VERSION 5.7 ;
  NOWIREEXTENSIONATPIN ON ;
  DIVIDERCHAR "/" ;
  BUSBITCHARS "[]" ;
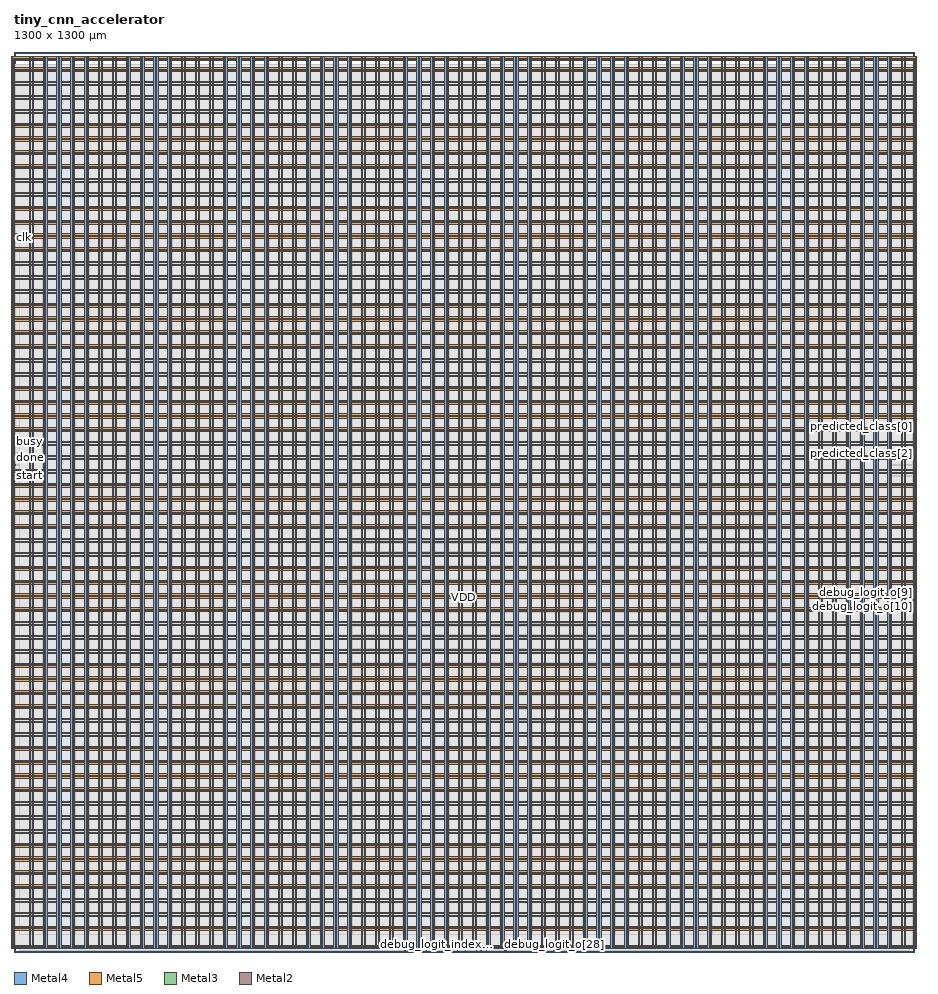
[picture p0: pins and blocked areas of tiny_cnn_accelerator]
MACRO tiny_cnn_accelerator
  CLASS BLOCK ;
  FOREIGN tiny_cnn_accelerator ;
  ORIGIN 0.000 0.000 ;
  SIZE 1300.000 BY 1300.000 ;
  PIN VDD
    DIRECTION INOUT ;
    USE POWER ;
    PORT
      LAYER Metal4 ;
        RECT -1.280 7.680 0.720 1289.840 ;
    END
    PORT
      LAYER Metal4 ;
        RECT 1299.040 7.680 1301.040 1289.840 ;
    END
    PORT
      LAYER Metal5 ;
        RECT -1.280 7.680 1301.040 9.680 ;
    END
    PORT
      LAYER Metal5 ;
        RECT -1.280 1287.840 1301.040 1289.840 ;
    END
    PORT
      LAYER Metal4 ;
        RECT 22.040 4.680 24.040 1292.840 ;
    END
    PORT
      LAYER Metal4 ;
        RECT 42.040 4.680 44.040 1292.840 ;
    END
    PORT
      LAYER Metal4 ;
        RECT 62.040 4.680 64.040 1292.840 ;
    END
    PORT
      LAYER Metal4 ;
        RECT 82.040 4.680 84.040 1292.840 ;
    END
    PORT
      LAYER Metal4 ;
        RECT 102.040 4.680 104.040 1292.840 ;
    END
    PORT
      LAYER Metal4 ;
        RECT 122.040 4.680 124.040 1292.840 ;
    END
    PORT
      LAYER Metal4 ;
        RECT 142.040 4.680 144.040 1292.840 ;
    END
    PORT
      LAYER Metal4 ;
        RECT 162.040 4.680 164.040 1292.840 ;
    END
    PORT
      LAYER Metal4 ;
        RECT 182.040 4.680 184.040 1292.840 ;
    END
    PORT
      LAYER Metal4 ;
        RECT 202.040 4.680 204.040 1292.840 ;
    END
    PORT
      LAYER Metal4 ;
        RECT 222.040 4.680 224.040 1292.840 ;
    END
    PORT
      LAYER Metal4 ;
        RECT 242.040 4.680 244.040 1292.840 ;
    END
    PORT
      LAYER Metal4 ;
        RECT 262.040 4.680 264.040 1292.840 ;
    END
    PORT
      LAYER Metal4 ;
        RECT 282.040 4.680 284.040 1292.840 ;
    END
    PORT
      LAYER Metal4 ;
        RECT 302.040 4.680 304.040 1292.840 ;
    END
    PORT
      LAYER Metal4 ;
        RECT 322.040 4.680 324.040 1292.840 ;
    END
    PORT
      LAYER Metal4 ;
        RECT 342.040 4.680 344.040 1292.840 ;
    END
    PORT
      LAYER Metal4 ;
        RECT 362.040 4.680 364.040 1292.840 ;
    END
    PORT
      LAYER Metal4 ;
        RECT 382.040 4.680 384.040 1292.840 ;
    END
    PORT
      LAYER Metal4 ;
        RECT 402.040 4.680 404.040 1292.840 ;
    END
    PORT
      LAYER Metal4 ;
        RECT 422.040 4.680 424.040 1292.840 ;
    END
    PORT
      LAYER Metal4 ;
        RECT 442.040 4.680 444.040 1292.840 ;
    END
    PORT
      LAYER Metal4 ;
        RECT 462.040 4.680 464.040 1292.840 ;
    END
    PORT
      LAYER Metal4 ;
        RECT 482.040 4.680 484.040 1292.840 ;
    END
    PORT
      LAYER Metal4 ;
        RECT 502.040 4.680 504.040 1292.840 ;
    END
    PORT
      LAYER Metal4 ;
        RECT 522.040 4.680 524.040 1292.840 ;
    END
    PORT
      LAYER Metal4 ;
        RECT 542.040 4.680 544.040 1292.840 ;
    END
    PORT
      LAYER Metal4 ;
        RECT 562.040 4.680 564.040 1292.840 ;
    END
    PORT
      LAYER Metal4 ;
        RECT 582.040 4.680 584.040 1292.840 ;
    END
    PORT
      LAYER Metal4 ;
        RECT 602.040 4.680 604.040 1292.840 ;
    END
    PORT
      LAYER Metal4 ;
        RECT 622.040 4.680 624.040 1292.840 ;
    END
    PORT
      LAYER Metal4 ;
        RECT 642.040 4.680 644.040 1292.840 ;
    END
    PORT
      LAYER Metal4 ;
        RECT 662.040 4.680 664.040 1292.840 ;
    END
    PORT
      LAYER Metal4 ;
        RECT 682.040 4.680 684.040 1292.840 ;
    END
    PORT
      LAYER Metal4 ;
        RECT 702.040 4.680 704.040 1292.840 ;
    END
    PORT
      LAYER Metal4 ;
        RECT 722.040 4.680 724.040 1292.840 ;
    END
    PORT
      LAYER Metal4 ;
        RECT 742.040 4.680 744.040 1292.840 ;
    END
    PORT
      LAYER Metal4 ;
        RECT 762.040 4.680 764.040 1292.840 ;
    END
    PORT
      LAYER Metal4 ;
        RECT 782.040 4.680 784.040 1292.840 ;
    END
    PORT
      LAYER Metal4 ;
        RECT 802.040 4.680 804.040 1292.840 ;
    END
    PORT
      LAYER Metal4 ;
        RECT 822.040 4.680 824.040 1292.840 ;
    END
    PORT
      LAYER Metal4 ;
        RECT 842.040 4.680 844.040 1292.840 ;
    END
    PORT
      LAYER Metal4 ;
        RECT 862.040 4.680 864.040 1292.840 ;
    END
    PORT
      LAYER Metal4 ;
        RECT 882.040 4.680 884.040 1292.840 ;
    END
    PORT
      LAYER Metal4 ;
        RECT 902.040 4.680 904.040 1292.840 ;
    END
    PORT
      LAYER Metal4 ;
        RECT 922.040 4.680 924.040 1292.840 ;
    END
    PORT
      LAYER Metal4 ;
        RECT 942.040 4.680 944.040 1292.840 ;
    END
    PORT
      LAYER Metal4 ;
        RECT 962.040 4.680 964.040 1292.840 ;
    END
    PORT
      LAYER Metal4 ;
        RECT 982.040 4.680 984.040 1292.840 ;
    END
    PORT
      LAYER Metal4 ;
        RECT 1002.040 4.680 1004.040 1292.840 ;
    END
    PORT
      LAYER Metal4 ;
        RECT 1022.040 4.680 1024.040 1292.840 ;
    END
    PORT
      LAYER Metal4 ;
        RECT 1042.040 4.680 1044.040 1292.840 ;
    END
    PORT
      LAYER Metal4 ;
        RECT 1062.040 4.680 1064.040 1292.840 ;
    END
    PORT
      LAYER Metal4 ;
        RECT 1082.040 4.680 1084.040 1292.840 ;
    END
    PORT
      LAYER Metal4 ;
        RECT 1102.040 4.680 1104.040 1292.840 ;
    END
    PORT
      LAYER Metal4 ;
        RECT 1122.040 4.680 1124.040 1292.840 ;
    END
    PORT
      LAYER Metal4 ;
        RECT 1142.040 4.680 1144.040 1292.840 ;
    END
    PORT
      LAYER Metal4 ;
        RECT 1162.040 4.680 1164.040 1292.840 ;
    END
    PORT
      LAYER Metal4 ;
        RECT 1182.040 4.680 1184.040 1292.840 ;
    END
    PORT
      LAYER Metal4 ;
        RECT 1202.040 4.680 1204.040 1292.840 ;
    END
    PORT
      LAYER Metal4 ;
        RECT 1222.040 4.680 1224.040 1292.840 ;
    END
    PORT
      LAYER Metal4 ;
        RECT 1242.040 4.680 1244.040 1292.840 ;
    END
    PORT
      LAYER Metal4 ;
        RECT 1262.040 4.680 1264.040 1292.840 ;
    END
    PORT
      LAYER Metal4 ;
        RECT 1282.040 4.680 1284.040 1292.840 ;
    END
    PORT
      LAYER Metal5 ;
        RECT -4.280 31.330 1304.040 33.330 ;
    END
    PORT
      LAYER Metal5 ;
        RECT -4.280 51.330 1304.040 53.330 ;
    END
    PORT
      LAYER Metal5 ;
        RECT -4.280 71.330 1304.040 73.330 ;
    END
    PORT
      LAYER Metal5 ;
        RECT -4.280 91.330 1304.040 93.330 ;
    END
    PORT
      LAYER Metal5 ;
        RECT -4.280 111.330 1304.040 113.330 ;
    END
    PORT
      LAYER Metal5 ;
        RECT -4.280 131.330 1304.040 133.330 ;
    END
    PORT
      LAYER Metal5 ;
        RECT -4.280 151.330 1304.040 153.330 ;
    END
    PORT
      LAYER Metal5 ;
        RECT -4.280 171.330 1304.040 173.330 ;
    END
    PORT
      LAYER Metal5 ;
        RECT -4.280 191.330 1304.040 193.330 ;
    END
    PORT
      LAYER Metal5 ;
        RECT -4.280 211.330 1304.040 213.330 ;
    END
    PORT
      LAYER Metal5 ;
        RECT -4.280 231.330 1304.040 233.330 ;
    END
    PORT
      LAYER Metal5 ;
        RECT -4.280 251.330 1304.040 253.330 ;
    END
    PORT
      LAYER Metal5 ;
        RECT -4.280 271.330 1304.040 273.330 ;
    END
    PORT
      LAYER Metal5 ;
        RECT -4.280 291.330 1304.040 293.330 ;
    END
    PORT
      LAYER Metal5 ;
        RECT -4.280 311.330 1304.040 313.330 ;
    END
    PORT
      LAYER Metal5 ;
        RECT -4.280 331.330 1304.040 333.330 ;
    END
    PORT
      LAYER Metal5 ;
        RECT -4.280 351.330 1304.040 353.330 ;
    END
    PORT
      LAYER Metal5 ;
        RECT -4.280 371.330 1304.040 373.330 ;
    END
    PORT
      LAYER Metal5 ;
        RECT -4.280 391.330 1304.040 393.330 ;
    END
    PORT
      LAYER Metal5 ;
        RECT -4.280 411.330 1304.040 413.330 ;
    END
    PORT
      LAYER Metal5 ;
        RECT -4.280 431.330 1304.040 433.330 ;
    END
    PORT
      LAYER Metal5 ;
        RECT -4.280 451.330 1304.040 453.330 ;
    END
    PORT
      LAYER Metal5 ;
        RECT -4.280 471.330 1304.040 473.330 ;
    END
    PORT
      LAYER Metal5 ;
        RECT -4.280 491.330 1304.040 493.330 ;
    END
    PORT
      LAYER Metal5 ;
        RECT -4.280 511.330 1304.040 513.330 ;
    END
    PORT
      LAYER Metal5 ;
        RECT -4.280 531.330 1304.040 533.330 ;
    END
    PORT
      LAYER Metal5 ;
        RECT -4.280 551.330 1304.040 553.330 ;
    END
    PORT
      LAYER Metal5 ;
        RECT -4.280 571.330 1304.040 573.330 ;
    END
    PORT
      LAYER Metal5 ;
        RECT -4.280 591.330 1304.040 593.330 ;
    END
    PORT
      LAYER Metal5 ;
        RECT -4.280 611.330 1304.040 613.330 ;
    END
    PORT
      LAYER Metal5 ;
        RECT -4.280 631.330 1304.040 633.330 ;
    END
    PORT
      LAYER Metal5 ;
        RECT -4.280 651.330 1304.040 653.330 ;
    END
    PORT
      LAYER Metal5 ;
        RECT -4.280 671.330 1304.040 673.330 ;
    END
    PORT
      LAYER Metal5 ;
        RECT -4.280 691.330 1304.040 693.330 ;
    END
    PORT
      LAYER Metal5 ;
        RECT -4.280 711.330 1304.040 713.330 ;
    END
    PORT
      LAYER Metal5 ;
        RECT -4.280 731.330 1304.040 733.330 ;
    END
    PORT
      LAYER Metal5 ;
        RECT -4.280 751.330 1304.040 753.330 ;
    END
    PORT
      LAYER Metal5 ;
        RECT -4.280 771.330 1304.040 773.330 ;
    END
    PORT
      LAYER Metal5 ;
        RECT -4.280 791.330 1304.040 793.330 ;
    END
    PORT
      LAYER Metal5 ;
        RECT -4.280 811.330 1304.040 813.330 ;
    END
    PORT
      LAYER Metal5 ;
        RECT -4.280 831.330 1304.040 833.330 ;
    END
    PORT
      LAYER Metal5 ;
        RECT -4.280 851.330 1304.040 853.330 ;
    END
    PORT
      LAYER Metal5 ;
        RECT -4.280 871.330 1304.040 873.330 ;
    END
    PORT
      LAYER Metal5 ;
        RECT -4.280 891.330 1304.040 893.330 ;
    END
    PORT
      LAYER Metal5 ;
        RECT -4.280 911.330 1304.040 913.330 ;
    END
    PORT
      LAYER Metal5 ;
        RECT -4.280 931.330 1304.040 933.330 ;
    END
    PORT
      LAYER Metal5 ;
        RECT -4.280 951.330 1304.040 953.330 ;
    END
    PORT
      LAYER Metal5 ;
        RECT -4.280 971.330 1304.040 973.330 ;
    END
    PORT
      LAYER Metal5 ;
        RECT -4.280 991.330 1304.040 993.330 ;
    END
    PORT
      LAYER Metal5 ;
        RECT -4.280 1011.330 1304.040 1013.330 ;
    END
    PORT
      LAYER Metal5 ;
        RECT -4.280 1031.330 1304.040 1033.330 ;
    END
    PORT
      LAYER Metal5 ;
        RECT -4.280 1051.330 1304.040 1053.330 ;
    END
    PORT
      LAYER Metal5 ;
        RECT -4.280 1071.330 1304.040 1073.330 ;
    END
    PORT
      LAYER Metal5 ;
        RECT -4.280 1091.330 1304.040 1093.330 ;
    END
    PORT
      LAYER Metal5 ;
        RECT -4.280 1111.330 1304.040 1113.330 ;
    END
    PORT
      LAYER Metal5 ;
        RECT -4.280 1131.330 1304.040 1133.330 ;
    END
    PORT
      LAYER Metal5 ;
        RECT -4.280 1151.330 1304.040 1153.330 ;
    END
    PORT
      LAYER Metal5 ;
        RECT -4.280 1171.330 1304.040 1173.330 ;
    END
    PORT
      LAYER Metal5 ;
        RECT -4.280 1191.330 1304.040 1193.330 ;
    END
    PORT
      LAYER Metal5 ;
        RECT -4.280 1211.330 1304.040 1213.330 ;
    END
    PORT
      LAYER Metal5 ;
        RECT -4.280 1231.330 1304.040 1233.330 ;
    END
    PORT
      LAYER Metal5 ;
        RECT -4.280 1251.330 1304.040 1253.330 ;
    END
    PORT
      LAYER Metal5 ;
        RECT -4.280 1271.330 1304.040 1273.330 ;
    END
  END VDD
  PIN VSS
    DIRECTION INOUT ;
    USE GROUND ;
    PORT
      LAYER Metal4 ;
        RECT -4.280 4.680 -2.280 1292.840 ;
    END
    PORT
      LAYER Metal4 ;
        RECT 1302.040 4.680 1304.040 1292.840 ;
    END
    PORT
      LAYER Metal5 ;
        RECT -4.280 4.680 1304.040 6.680 ;
    END
    PORT
      LAYER Metal5 ;
        RECT -4.280 1290.840 1304.040 1292.840 ;
    END
    PORT
      LAYER Metal4 ;
        RECT 26.040 4.680 28.040 1292.840 ;
    END
    PORT
      LAYER Metal4 ;
        RECT 46.040 4.680 48.040 1292.840 ;
    END
    PORT
      LAYER Metal4 ;
        RECT 66.040 4.680 68.040 1292.840 ;
    END
    PORT
      LAYER Metal4 ;
        RECT 86.040 4.680 88.040 1292.840 ;
    END
    PORT
      LAYER Metal4 ;
        RECT 106.040 4.680 108.040 1292.840 ;
    END
    PORT
      LAYER Metal4 ;
        RECT 126.040 4.680 128.040 1292.840 ;
    END
    PORT
      LAYER Metal4 ;
        RECT 146.040 4.680 148.040 1292.840 ;
    END
    PORT
      LAYER Metal4 ;
        RECT 166.040 4.680 168.040 1292.840 ;
    END
    PORT
      LAYER Metal4 ;
        RECT 186.040 4.680 188.040 1292.840 ;
    END
    PORT
      LAYER Metal4 ;
        RECT 206.040 4.680 208.040 1292.840 ;
    END
    PORT
      LAYER Metal4 ;
        RECT 226.040 4.680 228.040 1292.840 ;
    END
    PORT
      LAYER Metal4 ;
        RECT 246.040 4.680 248.040 1292.840 ;
    END
    PORT
      LAYER Metal4 ;
        RECT 266.040 4.680 268.040 1292.840 ;
    END
    PORT
      LAYER Metal4 ;
        RECT 286.040 4.680 288.040 1292.840 ;
    END
    PORT
      LAYER Metal4 ;
        RECT 306.040 4.680 308.040 1292.840 ;
    END
    PORT
      LAYER Metal4 ;
        RECT 326.040 4.680 328.040 1292.840 ;
    END
    PORT
      LAYER Metal4 ;
        RECT 346.040 4.680 348.040 1292.840 ;
    END
    PORT
      LAYER Metal4 ;
        RECT 366.040 4.680 368.040 1292.840 ;
    END
    PORT
      LAYER Metal4 ;
        RECT 386.040 4.680 388.040 1292.840 ;
    END
    PORT
      LAYER Metal4 ;
        RECT 406.040 4.680 408.040 1292.840 ;
    END
    PORT
      LAYER Metal4 ;
        RECT 426.040 4.680 428.040 1292.840 ;
    END
    PORT
      LAYER Metal4 ;
        RECT 446.040 4.680 448.040 1292.840 ;
    END
    PORT
      LAYER Metal4 ;
        RECT 466.040 4.680 468.040 1292.840 ;
    END
    PORT
      LAYER Metal4 ;
        RECT 486.040 4.680 488.040 1292.840 ;
    END
    PORT
      LAYER Metal4 ;
        RECT 506.040 4.680 508.040 1292.840 ;
    END
    PORT
      LAYER Metal4 ;
        RECT 526.040 4.680 528.040 1292.840 ;
    END
    PORT
      LAYER Metal4 ;
        RECT 546.040 4.680 548.040 1292.840 ;
    END
    PORT
      LAYER Metal4 ;
        RECT 566.040 4.680 568.040 1292.840 ;
    END
    PORT
      LAYER Metal4 ;
        RECT 586.040 4.680 588.040 1292.840 ;
    END
    PORT
      LAYER Metal4 ;
        RECT 606.040 4.680 608.040 1292.840 ;
    END
    PORT
      LAYER Metal4 ;
        RECT 626.040 4.680 628.040 1292.840 ;
    END
    PORT
      LAYER Metal4 ;
        RECT 646.040 4.680 648.040 1292.840 ;
    END
    PORT
      LAYER Metal4 ;
        RECT 666.040 4.680 668.040 1292.840 ;
    END
    PORT
      LAYER Metal4 ;
        RECT 686.040 4.680 688.040 1292.840 ;
    END
    PORT
      LAYER Metal4 ;
        RECT 706.040 4.680 708.040 1292.840 ;
    END
    PORT
      LAYER Metal4 ;
        RECT 726.040 4.680 728.040 1292.840 ;
    END
    PORT
      LAYER Metal4 ;
        RECT 746.040 4.680 748.040 1292.840 ;
    END
    PORT
      LAYER Metal4 ;
        RECT 766.040 4.680 768.040 1292.840 ;
    END
    PORT
      LAYER Metal4 ;
        RECT 786.040 4.680 788.040 1292.840 ;
    END
    PORT
      LAYER Metal4 ;
        RECT 806.040 4.680 808.040 1292.840 ;
    END
    PORT
      LAYER Metal4 ;
        RECT 826.040 4.680 828.040 1292.840 ;
    END
    PORT
      LAYER Metal4 ;
        RECT 846.040 4.680 848.040 1292.840 ;
    END
    PORT
      LAYER Metal4 ;
        RECT 866.040 4.680 868.040 1292.840 ;
    END
    PORT
      LAYER Metal4 ;
        RECT 886.040 4.680 888.040 1292.840 ;
    END
    PORT
      LAYER Metal4 ;
        RECT 906.040 4.680 908.040 1292.840 ;
    END
    PORT
      LAYER Metal4 ;
        RECT 926.040 4.680 928.040 1292.840 ;
    END
    PORT
      LAYER Metal4 ;
        RECT 946.040 4.680 948.040 1292.840 ;
    END
    PORT
      LAYER Metal4 ;
        RECT 966.040 4.680 968.040 1292.840 ;
    END
    PORT
      LAYER Metal4 ;
        RECT 986.040 4.680 988.040 1292.840 ;
    END
    PORT
      LAYER Metal4 ;
        RECT 1006.040 4.680 1008.040 1292.840 ;
    END
    PORT
      LAYER Metal4 ;
        RECT 1026.040 4.680 1028.040 1292.840 ;
    END
    PORT
      LAYER Metal4 ;
        RECT 1046.040 4.680 1048.040 1292.840 ;
    END
    PORT
      LAYER Metal4 ;
        RECT 1066.040 4.680 1068.040 1292.840 ;
    END
    PORT
      LAYER Metal4 ;
        RECT 1086.040 4.680 1088.040 1292.840 ;
    END
    PORT
      LAYER Metal4 ;
        RECT 1106.040 4.680 1108.040 1292.840 ;
    END
    PORT
      LAYER Metal4 ;
        RECT 1126.040 4.680 1128.040 1292.840 ;
    END
    PORT
      LAYER Metal4 ;
        RECT 1146.040 4.680 1148.040 1292.840 ;
    END
    PORT
      LAYER Metal4 ;
        RECT 1166.040 4.680 1168.040 1292.840 ;
    END
    PORT
      LAYER Metal4 ;
        RECT 1186.040 4.680 1188.040 1292.840 ;
    END
    PORT
      LAYER Metal4 ;
        RECT 1206.040 4.680 1208.040 1292.840 ;
    END
    PORT
      LAYER Metal4 ;
        RECT 1226.040 4.680 1228.040 1292.840 ;
    END
    PORT
      LAYER Metal4 ;
        RECT 1246.040 4.680 1248.040 1292.840 ;
    END
    PORT
      LAYER Metal4 ;
        RECT 1266.040 4.680 1268.040 1292.840 ;
    END
    PORT
      LAYER Metal4 ;
        RECT 1286.040 4.680 1288.040 1292.840 ;
    END
    PORT
      LAYER Metal5 ;
        RECT -4.280 35.330 1304.040 37.330 ;
    END
    PORT
      LAYER Metal5 ;
        RECT -4.280 55.330 1304.040 57.330 ;
    END
    PORT
      LAYER Metal5 ;
        RECT -4.280 75.330 1304.040 77.330 ;
    END
    PORT
      LAYER Metal5 ;
        RECT -4.280 95.330 1304.040 97.330 ;
    END
    PORT
      LAYER Metal5 ;
        RECT -4.280 115.330 1304.040 117.330 ;
    END
    PORT
      LAYER Metal5 ;
        RECT -4.280 135.330 1304.040 137.330 ;
    END
    PORT
      LAYER Metal5 ;
        RECT -4.280 155.330 1304.040 157.330 ;
    END
    PORT
      LAYER Metal5 ;
        RECT -4.280 175.330 1304.040 177.330 ;
    END
    PORT
      LAYER Metal5 ;
        RECT -4.280 195.330 1304.040 197.330 ;
    END
    PORT
      LAYER Metal5 ;
        RECT -4.280 215.330 1304.040 217.330 ;
    END
    PORT
      LAYER Metal5 ;
        RECT -4.280 235.330 1304.040 237.330 ;
    END
    PORT
      LAYER Metal5 ;
        RECT -4.280 255.330 1304.040 257.330 ;
    END
    PORT
      LAYER Metal5 ;
        RECT -4.280 275.330 1304.040 277.330 ;
    END
    PORT
      LAYER Metal5 ;
        RECT -4.280 295.330 1304.040 297.330 ;
    END
    PORT
      LAYER Metal5 ;
        RECT -4.280 315.330 1304.040 317.330 ;
    END
    PORT
      LAYER Metal5 ;
        RECT -4.280 335.330 1304.040 337.330 ;
    END
    PORT
      LAYER Metal5 ;
        RECT -4.280 355.330 1304.040 357.330 ;
    END
    PORT
      LAYER Metal5 ;
        RECT -4.280 375.330 1304.040 377.330 ;
    END
    PORT
      LAYER Metal5 ;
        RECT -4.280 395.330 1304.040 397.330 ;
    END
    PORT
      LAYER Metal5 ;
        RECT -4.280 415.330 1304.040 417.330 ;
    END
    PORT
      LAYER Metal5 ;
        RECT -4.280 435.330 1304.040 437.330 ;
    END
    PORT
      LAYER Metal5 ;
        RECT -4.280 455.330 1304.040 457.330 ;
    END
    PORT
      LAYER Metal5 ;
        RECT -4.280 475.330 1304.040 477.330 ;
    END
    PORT
      LAYER Metal5 ;
        RECT -4.280 495.330 1304.040 497.330 ;
    END
    PORT
      LAYER Metal5 ;
        RECT -4.280 515.330 1304.040 517.330 ;
    END
    PORT
      LAYER Metal5 ;
        RECT -4.280 535.330 1304.040 537.330 ;
    END
    PORT
      LAYER Metal5 ;
        RECT -4.280 555.330 1304.040 557.330 ;
    END
    PORT
      LAYER Metal5 ;
        RECT -4.280 575.330 1304.040 577.330 ;
    END
    PORT
      LAYER Metal5 ;
        RECT -4.280 595.330 1304.040 597.330 ;
    END
    PORT
      LAYER Metal5 ;
        RECT -4.280 615.330 1304.040 617.330 ;
    END
    PORT
      LAYER Metal5 ;
        RECT -4.280 635.330 1304.040 637.330 ;
    END
    PORT
      LAYER Metal5 ;
        RECT -4.280 655.330 1304.040 657.330 ;
    END
    PORT
      LAYER Metal5 ;
        RECT -4.280 675.330 1304.040 677.330 ;
    END
    PORT
      LAYER Metal5 ;
        RECT -4.280 695.330 1304.040 697.330 ;
    END
    PORT
      LAYER Metal5 ;
        RECT -4.280 715.330 1304.040 717.330 ;
    END
    PORT
      LAYER Metal5 ;
        RECT -4.280 735.330 1304.040 737.330 ;
    END
    PORT
      LAYER Metal5 ;
        RECT -4.280 755.330 1304.040 757.330 ;
    END
    PORT
      LAYER Metal5 ;
        RECT -4.280 775.330 1304.040 777.330 ;
    END
    PORT
      LAYER Metal5 ;
        RECT -4.280 795.330 1304.040 797.330 ;
    END
    PORT
      LAYER Metal5 ;
        RECT -4.280 815.330 1304.040 817.330 ;
    END
    PORT
      LAYER Metal5 ;
        RECT -4.280 835.330 1304.040 837.330 ;
    END
    PORT
      LAYER Metal5 ;
        RECT -4.280 855.330 1304.040 857.330 ;
    END
    PORT
      LAYER Metal5 ;
        RECT -4.280 875.330 1304.040 877.330 ;
    END
    PORT
      LAYER Metal5 ;
        RECT -4.280 895.330 1304.040 897.330 ;
    END
    PORT
      LAYER Metal5 ;
        RECT -4.280 915.330 1304.040 917.330 ;
    END
    PORT
      LAYER Metal5 ;
        RECT -4.280 935.330 1304.040 937.330 ;
    END
    PORT
      LAYER Metal5 ;
        RECT -4.280 955.330 1304.040 957.330 ;
    END
    PORT
      LAYER Metal5 ;
        RECT -4.280 975.330 1304.040 977.330 ;
    END
    PORT
      LAYER Metal5 ;
        RECT -4.280 995.330 1304.040 997.330 ;
    END
    PORT
      LAYER Metal5 ;
        RECT -4.280 1015.330 1304.040 1017.330 ;
    END
    PORT
      LAYER Metal5 ;
        RECT -4.280 1035.330 1304.040 1037.330 ;
    END
    PORT
      LAYER Metal5 ;
        RECT -4.280 1055.330 1304.040 1057.330 ;
    END
    PORT
      LAYER Metal5 ;
        RECT -4.280 1075.330 1304.040 1077.330 ;
    END
    PORT
      LAYER Metal5 ;
        RECT -4.280 1095.330 1304.040 1097.330 ;
    END
    PORT
      LAYER Metal5 ;
        RECT -4.280 1115.330 1304.040 1117.330 ;
    END
    PORT
      LAYER Metal5 ;
        RECT -4.280 1135.330 1304.040 1137.330 ;
    END
    PORT
      LAYER Metal5 ;
        RECT -4.280 1155.330 1304.040 1157.330 ;
    END
    PORT
      LAYER Metal5 ;
        RECT -4.280 1175.330 1304.040 1177.330 ;
    END
    PORT
      LAYER Metal5 ;
        RECT -4.280 1195.330 1304.040 1197.330 ;
    END
    PORT
      LAYER Metal5 ;
        RECT -4.280 1215.330 1304.040 1217.330 ;
    END
    PORT
      LAYER Metal5 ;
        RECT -4.280 1235.330 1304.040 1237.330 ;
    END
    PORT
      LAYER Metal5 ;
        RECT -4.280 1255.330 1304.040 1257.330 ;
    END
    PORT
      LAYER Metal5 ;
        RECT -4.280 1275.330 1304.040 1277.330 ;
    END
  END VSS
  PIN busy
    DIRECTION OUTPUT ;
    USE SIGNAL ;
    ANTENNADIFFAREA 0.897600 ;
    PORT
      LAYER Metal3 ;
        RECT 0.000 736.890 2.000 737.590 ;
    END
  END busy
  PIN clk
    DIRECTION INPUT ;
    USE SIGNAL ;
    ANTENNAGATEAREA 4.738000 ;
    PORT
      LAYER Metal3 ;
        RECT 0.000 1031.450 2.000 1032.150 ;
    END
  END clk
  PIN debug_logit_index_o[0]
    DIRECTION OUTPUT ;
    USE SIGNAL ;
    ANTENNADIFFAREA 0.897600 ;
    PORT
      LAYER Metal2 ;
        RECT 610.330 0.000 611.030 2.000 ;
    END
  END debug_logit_index_o[0]
  PIN debug_logit_index_o[1]
    DIRECTION OUTPUT ;
    USE SIGNAL ;
    ANTENNADIFFAREA 0.897600 ;
    PORT
      LAYER Metal2 ;
        RECT 609.210 0.000 609.910 2.000 ;
    END
  END debug_logit_index_o[1]
  PIN debug_logit_index_o[2]
    DIRECTION OUTPUT ;
    USE SIGNAL ;
    ANTENNADIFFAREA 0.897600 ;
    PORT
      LAYER Metal2 ;
        RECT 640.570 0.000 641.270 2.000 ;
    END
  END debug_logit_index_o[2]
  PIN debug_logit_index_o[3]
    DIRECTION OUTPUT ;
    USE SIGNAL ;
    ANTENNADIFFAREA 0.897600 ;
    PORT
      LAYER Metal2 ;
        RECT 667.450 0.000 668.150 2.000 ;
    END
  END debug_logit_index_o[3]
  PIN debug_logit_o[0]
    DIRECTION OUTPUT ;
    USE SIGNAL ;
    ANTENNADIFFAREA 0.897600 ;
    PORT
      LAYER Metal3 ;
        RECT 1298.000 517.370 1300.000 518.070 ;
    END
  END debug_logit_o[0]
  PIN debug_logit_o[10]
    DIRECTION OUTPUT ;
    USE SIGNAL ;
    ANTENNADIFFAREA 0.897600 ;
    PORT
      LAYER Metal3 ;
        RECT 1298.000 498.330 1300.000 499.030 ;
    END
  END debug_logit_o[10]
  PIN debug_logit_o[11]
    DIRECTION OUTPUT ;
    USE SIGNAL ;
    ANTENNADIFFAREA 0.897600 ;
    PORT
      LAYER Metal3 ;
        RECT 1298.000 502.810 1300.000 503.510 ;
    END
  END debug_logit_o[11]
  PIN debug_logit_o[12]
    DIRECTION OUTPUT ;
    USE SIGNAL ;
    ANTENNADIFFAREA 0.897600 ;
    PORT
      LAYER Metal3 ;
        RECT 1298.000 500.570 1300.000 501.270 ;
    END
  END debug_logit_o[12]
  PIN debug_logit_o[13]
    DIRECTION OUTPUT ;
    USE SIGNAL ;
    ANTENNADIFFAREA 0.897600 ;
    PORT
      LAYER Metal3 ;
        RECT 1298.000 501.690 1300.000 502.390 ;
    END
  END debug_logit_o[13]
  PIN debug_logit_o[14]
    DIRECTION OUTPUT ;
    USE SIGNAL ;
    ANTENNADIFFAREA 0.897600 ;
    PORT
      LAYER Metal3 ;
        RECT 1298.000 516.250 1300.000 516.950 ;
    END
  END debug_logit_o[14]
  PIN debug_logit_o[15]
    DIRECTION OUTPUT ;
    USE SIGNAL ;
    ANTENNADIFFAREA 0.897600 ;
    PORT
      LAYER Metal3 ;
        RECT 1298.000 514.010 1300.000 514.710 ;
    END
  END debug_logit_o[15]
  PIN debug_logit_o[16]
    DIRECTION OUTPUT ;
    USE SIGNAL ;
    ANTENNADIFFAREA 0.897600 ;
    PORT
      LAYER Metal2 ;
        RECT 708.890 0.000 709.590 2.000 ;
    END
  END debug_logit_o[16]
  PIN debug_logit_o[17]
    DIRECTION OUTPUT ;
    USE SIGNAL ;
    ANTENNADIFFAREA 0.897600 ;
    PORT
      LAYER Metal2 ;
        RECT 710.010 0.000 710.710 2.000 ;
    END
  END debug_logit_o[17]
  PIN debug_logit_o[18]
    DIRECTION OUTPUT ;
    USE SIGNAL ;
    ANTENNADIFFAREA 0.897600 ;
    PORT
      LAYER Metal2 ;
        RECT 651.770 0.000 652.470 2.000 ;
    END
  END debug_logit_o[18]
  PIN debug_logit_o[19]
    DIRECTION OUTPUT ;
    USE SIGNAL ;
    ANTENNADIFFAREA 0.897600 ;
    PORT
      LAYER Metal2 ;
        RECT 606.970 0.000 607.670 2.000 ;
    END
  END debug_logit_o[19]
  PIN debug_logit_o[1]
    DIRECTION OUTPUT ;
    USE SIGNAL ;
    ANTENNADIFFAREA 0.897600 ;
    PORT
      LAYER Metal3 ;
        RECT 1298.000 510.650 1300.000 511.350 ;
    END
  END debug_logit_o[1]
  PIN debug_logit_o[20]
    DIRECTION OUTPUT ;
    USE SIGNAL ;
    ANTENNADIFFAREA 0.897600 ;
    PORT
      LAYER Metal2 ;
        RECT 571.130 0.000 571.830 2.000 ;
    END
  END debug_logit_o[20]
  PIN debug_logit_o[21]
    DIRECTION OUTPUT ;
    USE SIGNAL ;
    ANTENNADIFFAREA 0.897600 ;
    PORT
      LAYER Metal2 ;
        RECT 568.890 0.000 569.590 2.000 ;
    END
  END debug_logit_o[21]
  PIN debug_logit_o[22]
    DIRECTION OUTPUT ;
    USE SIGNAL ;
    ANTENNADIFFAREA 0.897600 ;
    PORT
      LAYER Metal2 ;
        RECT 586.810 0.000 587.510 2.000 ;
    END
  END debug_logit_o[22]
  PIN debug_logit_o[23]
    DIRECTION OUTPUT ;
    USE SIGNAL ;
    ANTENNADIFFAREA 0.897600 ;
    PORT
      LAYER Metal2 ;
        RECT 595.770 0.000 596.470 2.000 ;
    END
  END debug_logit_o[23]
  PIN debug_logit_o[24]
    DIRECTION OUTPUT ;
    USE SIGNAL ;
    ANTENNADIFFAREA 0.897600 ;
    PORT
      LAYER Metal2 ;
        RECT 626.010 0.000 626.710 2.000 ;
    END
  END debug_logit_o[24]
  PIN debug_logit_o[25]
    DIRECTION OUTPUT ;
    USE SIGNAL ;
    ANTENNADIFFAREA 0.897600 ;
    PORT
      LAYER Metal2 ;
        RECT 629.370 0.000 630.070 2.000 ;
    END
  END debug_logit_o[25]
  PIN debug_logit_o[26]
    DIRECTION OUTPUT ;
    USE SIGNAL ;
    ANTENNADIFFAREA 0.897600 ;
    PORT
      LAYER Metal2 ;
        RECT 674.170 0.000 674.870 2.000 ;
    END
  END debug_logit_o[26]
  PIN debug_logit_o[27]
    DIRECTION OUTPUT ;
    USE SIGNAL ;
    ANTENNADIFFAREA 0.897600 ;
    PORT
      LAYER Metal2 ;
        RECT 682.010 0.000 682.710 2.000 ;
    END
  END debug_logit_o[27]
  PIN debug_logit_o[28]
    DIRECTION OUTPUT ;
    USE SIGNAL ;
    ANTENNADIFFAREA 0.897600 ;
    PORT
      LAYER Metal2 ;
        RECT 780.570 0.000 781.270 2.000 ;
    END
  END debug_logit_o[28]
  PIN debug_logit_o[29]
    DIRECTION OUTPUT ;
    USE SIGNAL ;
    ANTENNADIFFAREA 0.897600 ;
    PORT
      LAYER Metal2 ;
        RECT 779.450 0.000 780.150 2.000 ;
    END
  END debug_logit_o[29]
  PIN debug_logit_o[2]
    DIRECTION OUTPUT ;
    USE SIGNAL ;
    ANTENNADIFFAREA 0.897600 ;
    PORT
      LAYER Metal3 ;
        RECT 1298.000 507.290 1300.000 507.990 ;
    END
  END debug_logit_o[2]
  PIN debug_logit_o[30]
    DIRECTION OUTPUT ;
    USE SIGNAL ;
    ANTENNADIFFAREA 0.897600 ;
    PORT
      LAYER Metal3 ;
        RECT 1298.000 515.130 1300.000 515.830 ;
    END
  END debug_logit_o[30]
  PIN debug_logit_o[31]
    DIRECTION OUTPUT ;
    USE SIGNAL ;
    ANTENNADIFFAREA 0.897600 ;
    PORT
      LAYER Metal3 ;
        RECT 1298.000 512.890 1300.000 513.590 ;
    END
  END debug_logit_o[31]
  PIN debug_logit_o[3]
    DIRECTION OUTPUT ;
    USE SIGNAL ;
    ANTENNADIFFAREA 0.897600 ;
    PORT
      LAYER Metal3 ;
        RECT 1298.000 509.530 1300.000 510.230 ;
    END
  END debug_logit_o[3]
  PIN debug_logit_o[4]
    DIRECTION OUTPUT ;
    USE SIGNAL ;
    ANTENNADIFFAREA 0.897600 ;
    PORT
      LAYER Metal3 ;
        RECT 1298.000 499.450 1300.000 500.150 ;
    END
  END debug_logit_o[4]
  PIN debug_logit_o[5]
    DIRECTION OUTPUT ;
    USE SIGNAL ;
    ANTENNADIFFAREA 0.897600 ;
    PORT
      LAYER Metal3 ;
        RECT 1298.000 503.930 1300.000 504.630 ;
    END
  END debug_logit_o[5]
  PIN debug_logit_o[6]
    DIRECTION OUTPUT ;
    USE SIGNAL ;
    ANTENNADIFFAREA 0.897600 ;
    PORT
      LAYER Metal3 ;
        RECT 1298.000 506.170 1300.000 506.870 ;
    END
  END debug_logit_o[6]
  PIN debug_logit_o[7]
    DIRECTION OUTPUT ;
    USE SIGNAL ;
    ANTENNADIFFAREA 0.897600 ;
    PORT
      LAYER Metal3 ;
        RECT 1298.000 505.050 1300.000 505.750 ;
    END
  END debug_logit_o[7]
  PIN debug_logit_o[8]
    DIRECTION OUTPUT ;
    USE SIGNAL ;
    ANTENNADIFFAREA 0.897600 ;
    PORT
      LAYER Metal3 ;
        RECT 1298.000 511.770 1300.000 512.470 ;
    END
  END debug_logit_o[8]
  PIN debug_logit_o[9]
    DIRECTION OUTPUT ;
    USE SIGNAL ;
    ANTENNADIFFAREA 0.897600 ;
    PORT
      LAYER Metal3 ;
        RECT 1298.000 508.410 1300.000 509.110 ;
    END
  END debug_logit_o[9]
  PIN debug_logit_valid_o
    DIRECTION OUTPUT ;
    USE SIGNAL ;
    ANTENNADIFFAREA 0.897600 ;
    PORT
      LAYER Metal2 ;
        RECT 564.410 0.000 565.110 2.000 ;
    END
  END debug_logit_valid_o
  PIN done
    DIRECTION OUTPUT ;
    USE SIGNAL ;
    ANTENNADIFFAREA 0.897600 ;
    PORT
      LAYER Metal3 ;
        RECT 0.000 703.290 2.000 703.990 ;
    END
  END done
  PIN predicted_class[0]
    DIRECTION OUTPUT ;
    USE SIGNAL ;
    ANTENNADIFFAREA 0.897600 ;
    PORT
      LAYER Metal3 ;
        RECT 1298.000 759.290 1300.000 759.990 ;
    END
  END predicted_class[0]
  PIN predicted_class[1]
    DIRECTION OUTPUT ;
    USE SIGNAL ;
    ANTENNADIFFAREA 0.897600 ;
    PORT
      LAYER Metal3 ;
        RECT 1298.000 758.170 1300.000 758.870 ;
    END
  END predicted_class[1]
  PIN predicted_class[2]
    DIRECTION OUTPUT ;
    USE SIGNAL ;
    ANTENNADIFFAREA 0.897600 ;
    PORT
      LAYER Metal3 ;
        RECT 1298.000 720.090 1300.000 720.790 ;
    END
  END predicted_class[2]
  PIN predicted_class[3]
    DIRECTION OUTPUT ;
    USE SIGNAL ;
    ANTENNADIFFAREA 0.897600 ;
    PORT
      LAYER Metal3 ;
        RECT 1298.000 715.610 1300.000 716.310 ;
    END
  END predicted_class[3]
  PIN rst_n
    DIRECTION INPUT ;
    USE SIGNAL ;
    ANTENNAGATEAREA 0.498500 ;
    PORT
      LAYER Metal3 ;
        RECT 0.000 1030.330 2.000 1031.030 ;
    END
  END rst_n
  PIN start
    DIRECTION INPUT ;
    USE SIGNAL ;
    ANTENNAGATEAREA 0.498500 ;
    PORT
      LAYER Metal3 ;
        RECT 0.000 687.610 2.000 688.310 ;
    END
  END start
  OBS
      LAYER Nwell ;
        RECT 6.290 15.250 1293.470 1282.270 ;
      LAYER Metal1 ;
        RECT 6.720 15.380 1293.040 1282.140 ;
      LAYER Metal2 ;
        RECT 8.540 2.300 1292.900 1282.030 ;
        RECT 8.540 2.000 564.110 2.300 ;
        RECT 565.410 2.000 568.590 2.300 ;
        RECT 569.890 2.000 570.830 2.300 ;
        RECT 572.130 2.000 586.510 2.300 ;
        RECT 587.810 2.000 595.470 2.300 ;
        RECT 596.770 2.000 606.670 2.300 ;
        RECT 607.970 2.000 608.910 2.300 ;
        RECT 611.330 2.000 625.710 2.300 ;
        RECT 627.010 2.000 629.070 2.300 ;
        RECT 630.370 2.000 640.270 2.300 ;
        RECT 641.570 2.000 651.470 2.300 ;
        RECT 652.770 2.000 667.150 2.300 ;
        RECT 668.450 2.000 673.870 2.300 ;
        RECT 675.170 2.000 681.710 2.300 ;
        RECT 683.010 2.000 708.590 2.300 ;
        RECT 711.010 2.000 779.150 2.300 ;
        RECT 781.570 2.000 1292.900 2.300 ;
      LAYER Metal3 ;
        RECT 2.000 1032.450 1298.000 1281.980 ;
        RECT 2.300 1030.030 1298.000 1032.450 ;
        RECT 2.000 760.290 1298.000 1030.030 ;
        RECT 2.000 757.870 1297.700 760.290 ;
        RECT 2.000 737.890 1298.000 757.870 ;
        RECT 2.300 736.590 1298.000 737.890 ;
        RECT 2.000 721.090 1298.000 736.590 ;
        RECT 2.000 719.790 1297.700 721.090 ;
        RECT 2.000 716.610 1298.000 719.790 ;
        RECT 2.000 715.310 1297.700 716.610 ;
        RECT 2.000 704.290 1298.000 715.310 ;
        RECT 2.300 702.990 1298.000 704.290 ;
        RECT 2.000 688.610 1298.000 702.990 ;
        RECT 2.300 687.310 1298.000 688.610 ;
        RECT 2.000 518.370 1298.000 687.310 ;
        RECT 2.000 498.030 1297.700 518.370 ;
        RECT 2.000 8.540 1298.000 498.030 ;
      LAYER Metal4 ;
        RECT 7.420 25.290 21.740 1031.990 ;
        RECT 24.340 25.290 25.740 1031.990 ;
        RECT 28.340 25.290 41.740 1031.990 ;
        RECT 44.340 25.290 45.740 1031.990 ;
        RECT 48.340 25.290 61.740 1031.990 ;
        RECT 64.340 25.290 65.740 1031.990 ;
        RECT 68.340 25.290 81.740 1031.990 ;
        RECT 84.340 25.290 85.740 1031.990 ;
        RECT 88.340 25.290 101.740 1031.990 ;
        RECT 104.340 25.290 105.740 1031.990 ;
        RECT 108.340 25.290 121.740 1031.990 ;
        RECT 124.340 25.290 125.740 1031.990 ;
        RECT 128.340 25.290 141.740 1031.990 ;
        RECT 144.340 25.290 145.740 1031.990 ;
        RECT 148.340 25.290 161.740 1031.990 ;
        RECT 164.340 25.290 165.740 1031.990 ;
        RECT 168.340 25.290 181.740 1031.990 ;
        RECT 184.340 25.290 185.740 1031.990 ;
        RECT 188.340 25.290 201.740 1031.990 ;
        RECT 204.340 25.290 205.740 1031.990 ;
        RECT 208.340 25.290 221.740 1031.990 ;
        RECT 224.340 25.290 225.740 1031.990 ;
        RECT 228.340 25.290 241.740 1031.990 ;
        RECT 244.340 25.290 245.740 1031.990 ;
        RECT 248.340 25.290 261.740 1031.990 ;
        RECT 264.340 25.290 265.740 1031.990 ;
        RECT 268.340 25.290 281.740 1031.990 ;
        RECT 284.340 25.290 285.740 1031.990 ;
        RECT 288.340 25.290 301.740 1031.990 ;
        RECT 304.340 25.290 305.740 1031.990 ;
        RECT 308.340 25.290 321.740 1031.990 ;
        RECT 324.340 25.290 325.740 1031.990 ;
        RECT 328.340 25.290 341.740 1031.990 ;
        RECT 344.340 25.290 345.740 1031.990 ;
        RECT 348.340 25.290 361.740 1031.990 ;
        RECT 364.340 25.290 365.740 1031.990 ;
        RECT 368.340 25.290 381.740 1031.990 ;
        RECT 384.340 25.290 385.740 1031.990 ;
        RECT 388.340 25.290 401.740 1031.990 ;
        RECT 404.340 25.290 405.740 1031.990 ;
        RECT 408.340 25.290 421.740 1031.990 ;
        RECT 424.340 25.290 425.740 1031.990 ;
        RECT 428.340 25.290 441.740 1031.990 ;
        RECT 444.340 25.290 445.740 1031.990 ;
        RECT 448.340 25.290 461.740 1031.990 ;
        RECT 464.340 25.290 465.740 1031.990 ;
        RECT 468.340 25.290 481.740 1031.990 ;
        RECT 484.340 25.290 485.740 1031.990 ;
        RECT 488.340 25.290 501.740 1031.990 ;
        RECT 504.340 25.290 505.740 1031.990 ;
        RECT 508.340 25.290 521.740 1031.990 ;
        RECT 524.340 25.290 525.740 1031.990 ;
        RECT 528.340 25.290 541.740 1031.990 ;
        RECT 544.340 25.290 545.740 1031.990 ;
        RECT 548.340 25.290 561.740 1031.990 ;
        RECT 564.340 25.290 565.740 1031.990 ;
        RECT 568.340 25.290 581.740 1031.990 ;
        RECT 584.340 25.290 585.740 1031.990 ;
        RECT 588.340 25.290 601.740 1031.990 ;
        RECT 604.340 25.290 605.740 1031.990 ;
        RECT 608.340 25.290 621.740 1031.990 ;
        RECT 624.340 25.290 625.740 1031.990 ;
        RECT 628.340 25.290 641.740 1031.990 ;
        RECT 644.340 25.290 645.740 1031.990 ;
        RECT 648.340 25.290 661.740 1031.990 ;
        RECT 664.340 25.290 665.740 1031.990 ;
        RECT 668.340 25.290 681.740 1031.990 ;
        RECT 684.340 25.290 685.740 1031.990 ;
        RECT 688.340 25.290 701.740 1031.990 ;
        RECT 704.340 25.290 705.740 1031.990 ;
        RECT 708.340 25.290 721.740 1031.990 ;
        RECT 724.340 25.290 725.740 1031.990 ;
        RECT 728.340 25.290 741.740 1031.990 ;
        RECT 744.340 25.290 745.740 1031.990 ;
        RECT 748.340 25.290 761.740 1031.990 ;
        RECT 764.340 25.290 765.740 1031.990 ;
        RECT 768.340 25.290 781.740 1031.990 ;
        RECT 784.340 25.290 785.740 1031.990 ;
        RECT 788.340 25.290 801.740 1031.990 ;
        RECT 804.340 25.290 805.740 1031.990 ;
        RECT 808.340 25.290 821.740 1031.990 ;
        RECT 824.340 25.290 825.740 1031.990 ;
        RECT 828.340 25.290 841.740 1031.990 ;
        RECT 844.340 25.290 845.740 1031.990 ;
        RECT 848.340 25.290 861.740 1031.990 ;
        RECT 864.340 25.290 865.740 1031.990 ;
        RECT 868.340 25.290 881.740 1031.990 ;
        RECT 884.340 25.290 885.740 1031.990 ;
        RECT 888.340 25.290 901.740 1031.990 ;
        RECT 904.340 25.290 905.740 1031.990 ;
        RECT 908.340 25.290 921.740 1031.990 ;
        RECT 924.340 25.290 925.740 1031.990 ;
        RECT 928.340 25.290 941.740 1031.990 ;
        RECT 944.340 25.290 945.740 1031.990 ;
        RECT 948.340 25.290 961.740 1031.990 ;
        RECT 964.340 25.290 965.740 1031.990 ;
        RECT 968.340 25.290 981.740 1031.990 ;
        RECT 984.340 25.290 985.740 1031.990 ;
        RECT 988.340 25.290 1001.740 1031.990 ;
        RECT 1004.340 25.290 1005.740 1031.990 ;
        RECT 1008.340 25.290 1021.740 1031.990 ;
        RECT 1024.340 25.290 1025.740 1031.990 ;
        RECT 1028.340 25.290 1041.740 1031.990 ;
        RECT 1044.340 25.290 1045.740 1031.990 ;
        RECT 1048.340 25.290 1061.740 1031.990 ;
        RECT 1064.340 25.290 1065.740 1031.990 ;
        RECT 1068.340 25.290 1081.740 1031.990 ;
        RECT 1084.340 25.290 1085.740 1031.990 ;
        RECT 1088.340 25.290 1101.740 1031.990 ;
        RECT 1104.340 25.290 1105.740 1031.990 ;
        RECT 1108.340 25.290 1121.740 1031.990 ;
        RECT 1124.340 25.290 1125.740 1031.990 ;
        RECT 1128.340 25.290 1141.740 1031.990 ;
        RECT 1144.340 25.290 1145.740 1031.990 ;
        RECT 1148.340 25.290 1161.740 1031.990 ;
        RECT 1164.340 25.290 1165.740 1031.990 ;
        RECT 1168.340 25.290 1181.740 1031.990 ;
        RECT 1184.340 25.290 1185.740 1031.990 ;
        RECT 1188.340 25.290 1201.740 1031.990 ;
        RECT 1204.340 25.290 1205.740 1031.990 ;
        RECT 1208.340 25.290 1221.740 1031.990 ;
        RECT 1224.340 25.290 1225.740 1031.990 ;
        RECT 1228.340 25.290 1241.740 1031.990 ;
        RECT 1244.340 25.290 1245.740 1031.990 ;
        RECT 1248.340 25.290 1261.740 1031.990 ;
        RECT 1264.340 25.290 1265.460 1031.990 ;
      LAYER Metal5 ;
        RECT 488.380 673.930 1101.460 674.730 ;
        RECT 488.380 657.930 1101.460 670.730 ;
        RECT 488.380 653.930 1101.460 654.730 ;
        RECT 488.380 637.930 1101.460 650.730 ;
        RECT 488.380 633.930 1101.460 634.730 ;
        RECT 488.380 617.930 1101.460 630.730 ;
        RECT 488.380 613.930 1101.460 614.730 ;
        RECT 488.380 597.930 1101.460 610.730 ;
        RECT 488.380 593.930 1101.460 594.730 ;
        RECT 488.380 577.930 1101.460 590.730 ;
        RECT 488.380 573.930 1101.460 574.730 ;
        RECT 488.380 557.930 1101.460 570.730 ;
        RECT 488.380 553.930 1101.460 554.730 ;
        RECT 488.380 537.930 1101.460 550.730 ;
        RECT 488.380 533.930 1101.460 534.730 ;
        RECT 488.380 517.930 1101.460 530.730 ;
        RECT 488.380 513.930 1101.460 514.730 ;
        RECT 488.380 497.930 1101.460 510.730 ;
        RECT 488.380 493.930 1101.460 494.730 ;
        RECT 488.380 477.930 1101.460 490.730 ;
        RECT 488.380 473.930 1101.460 474.730 ;
        RECT 488.380 457.930 1101.460 470.730 ;
        RECT 488.380 453.930 1101.460 454.730 ;
        RECT 488.380 437.930 1101.460 450.730 ;
        RECT 488.380 433.930 1101.460 434.730 ;
        RECT 488.380 417.930 1101.460 430.730 ;
        RECT 488.380 413.930 1101.460 414.730 ;
        RECT 488.380 397.930 1101.460 410.730 ;
        RECT 488.380 393.930 1101.460 394.730 ;
        RECT 488.380 377.930 1101.460 390.730 ;
        RECT 488.380 373.930 1101.460 374.730 ;
        RECT 488.380 357.930 1101.460 370.730 ;
        RECT 488.380 353.930 1101.460 354.730 ;
        RECT 488.380 337.930 1101.460 350.730 ;
        RECT 488.380 334.130 1101.460 334.730 ;
  END
END tiny_cnn_accelerator
END LIBRARY

